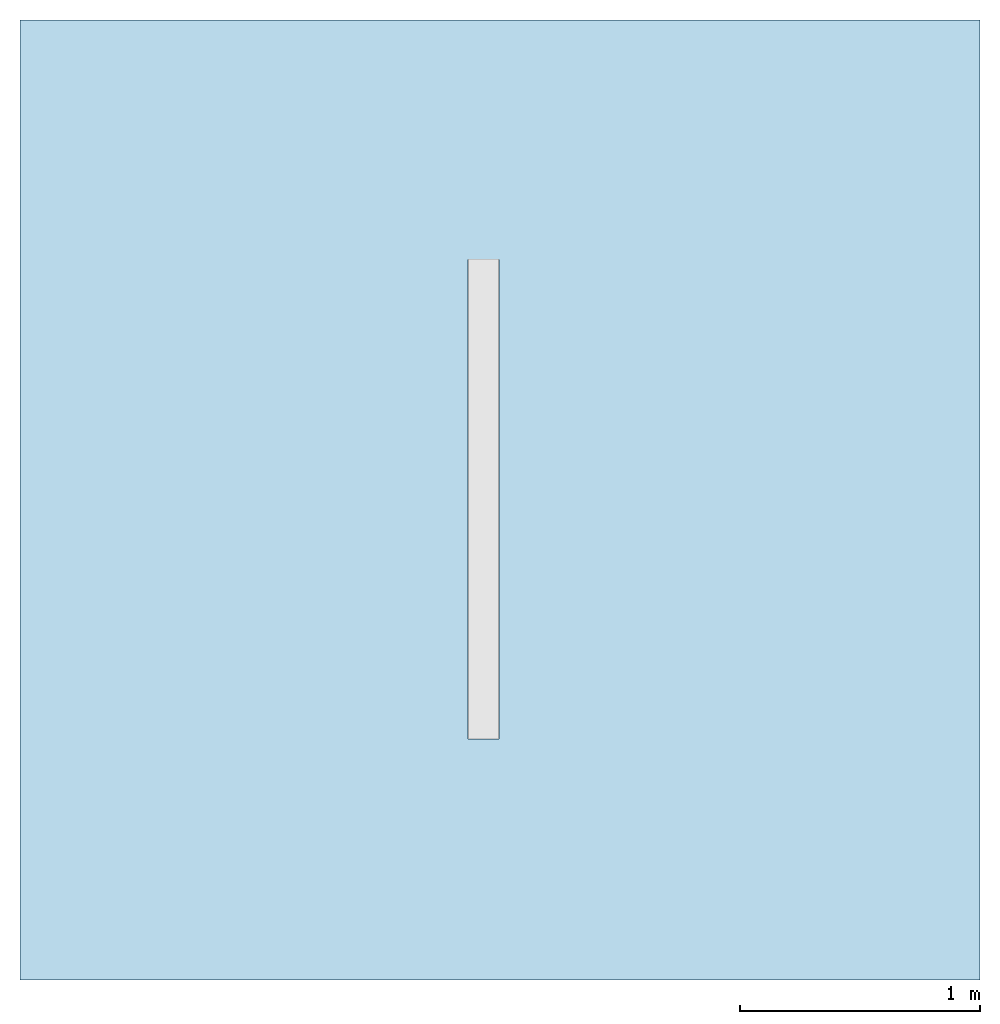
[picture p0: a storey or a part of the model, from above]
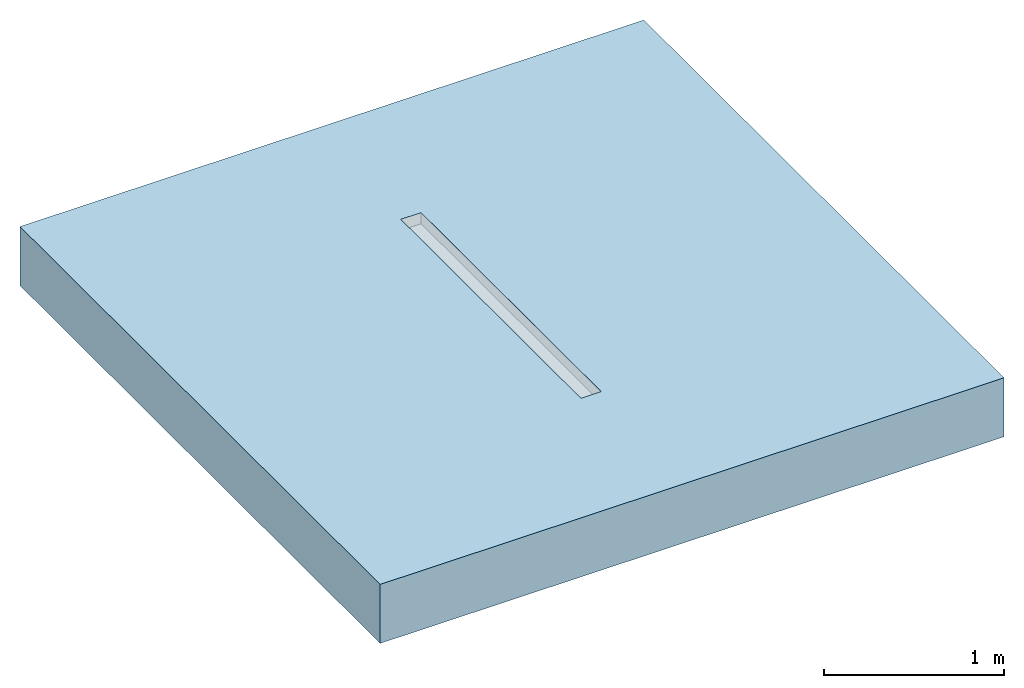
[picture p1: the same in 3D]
Properties of the parts of a building model (IFC2X3)

# File
Description: ViewDefinition [CoordinationView]
File name: Project Number
Time: 2014-06-06T14:55:17
Written by: The EXPRESS Data Manager Version 5.01.0100.02.64mod : 6 Jun 2012
Made in: 20130308_1515(x64) - Exporter 2014.0.2013.0308 - Default UI
Comment: STEP Physical File produced by: The EXPRESS Data Manager Version 5.01.0100.02.64mod : 6 Jun 2012 * Module: EDMstepFileFactory/EDMstandAlone * Creation date: Fri Jun 06 14:55:17 2014 * Host: IN-BLR-PC-0010 * Database: C:\Users\palleri\AppData\Local\Temp\{A1F0F1A7-A8EC-4AB1-B1F4-9037619E79AD}\ifc * Database version: 5507 * Database creation date: Fri Jun 06 14:55:12 2014 * Schema: IFC2X3 * Model: DataRepository.ifc * Model creation date: Fri Jun 06 14:55:12 2014 * Header model: DataRepository.ifc_HeaderModel * Header model creation date: Fri Jun 06 14:55:12 2014 * EDMuser: sdai-user * EDMgroup: sdai-group * License ID and type: 5605 : Permanent license. Expiry date: * EDMstepFileFactory options: 020000

# IfcProject, Project Number
LongName: Project Name; Phase: Project Status

# IfcSite, Default
RefLatitude: 42, 21, 30, 344238; RefLongitude: -71, -3, -35, -194702; RefElevation: 0 mm

# IfcBuilding
Pset_BuildingCommon - NumberOfStoreys: 1
Other - Project Issue Date: Issue Date; Client Name: Owner; Project Number: Project Number; Project Name: Project Name; Project Address: ## Street City, State Zip; Project Status: Project Status

# IfcBuildingStorey, Level 1
LongName: Level 1; Elevation: 0 mm
Constraints - Elevation Base: Project Base Point; Elevation: 0 mm
Graphics - Symbol at End 2 Default: yes; Color: 0; Symbol at End 1 Default: no; Line Weight: 1; Line Pattern: Center; Symbol: M_Level Head - Circle: M_Level Head - Circle
Identity Data - Building Story: yes; Structural: no; Name: Level 1
Dimensions - Computation Height: 0 mm

# IfcFlowTerminal: 36980 - Fixed Height Channel - Shallow Section - 2000mm LG - Invert Depth 75mm, ACO Freedeck Fixed Height Channel Intermediate Section Galvanized Steel:36980 - Fixed Height Channel - Shallow Section - 2000mm LG - Invert Depth 75mm:310971
In: Level 1
Material: Galvanized Steel
Construction - End Plate Invert 2: no; 00276 - Grating - Slotted Grating - Galvanised Steel - 1000mm long: no; End Plate Invert 1: no; 00277 - Grating - Slotted Grating - Galvanised Steel - 500mm long: no; 36952 - Grating - Plain Mesh - Galvanised Steel - 500mm long: no; 36953 - Grating - Plain Mesh - Galvanised Steel - 1000mm long: yes
Identity Data - Mark: 28; Watermark2: This file is water marked and users are prohibited to reproduce, adapt, distribute this information; Watermarked By: www.acobd.com; Watermark1: This file is the property of ACO Technologies PLC; E-mail Sales: abdcommercial@aco.co.uk; E-mail Technical: abdtechnical@aco.co.uk; Watermarked With: BIM Manager Premium Suite; Address: ACO Business Centre, Caxton Road, Bedford, MK41 0LF; Telephone: +44 (0)1462 816666; Website: www.acobd.com; Manufacturer: ACO Building Drainage; Fax: +44 (0)1462 851490
Phasing - Phase Created: New Construction
Constraints - Moves With Nearby Elements: no; Level: Level: Level 1
Pset_ManufacturerTypeInformation - Manufacturer: ACO Building Drainage
General - Channel Recycled Material Content: 25 - 30 %; Channel Recyclable: Fully recyclable; Load Class: A15; Product Description: ACO FreeDeck Fixed Height Channel - Intermediate Section; NBS Specification: NBS Section R10 Gravity Rainwater Drainage Systems, Subsection 365; Channel Colour: Galvanised; Maintenance Guidelines: X:\Electronic Literature\ABD Electronic Literature\Roof and Balcony Drainage\ACO Freedeck Brochure.pdf; Product Standard: BS EN 1433:2002, CE marked; Product Code: 36980; Channel Material: Hot Dipped Galvanised Steel; Product Range: ACO Freedeck; Installation Guidelines: X:\Electronic Literature\ABD Electronic Literature\Roof and Balcony Drainage\ACO Freedeck Brochure.pdf; Price: POA - contact ACO; Weight (Kg): 4.8kg; Dimensions (LxWxH): 2000 x 130 x 75; Product Type: Linear Deck Drainage System
Model Properties - Grating Product Code 00277: Load Class A15 - Slotted Grating - 10 x 80mm Slot - Galvanized Steel - 500mm long - 1.0kg; Grating Product Code 00276: Load Class A15 - Slotted Grating - 10 x 80mm Slot - Galvanized Steel - 1000mm long - 2.2kg; Grating Product Code 36952: Load Class A15 - Mesh Grating - 14mm x 30mm Mesh - Galvanized Steel - 500mm long - 1.6kg; End Plate Product Code 36983: End Plate - Galvanized Steel for Invert Depth - 75mm - 0.07Kg; Grating Product Code 36953: Load Class A15 - Mesh Grating - 14mm x 30mm Mesh - Galvanized Steel - 1000mm long - 3.0kg
Other - Nos: 64; Side Void: 8
Materials and Finishes - Material: Galvanized Steel
Dimensions - Grating End Length: 2000 mm; Height: 75 mm; Channel End Length: -2000 mm

# IfcSlab: Floor:Generic Floor - 400mm, Floor:Generic Floor - 400mm:193825
In: Level 1
PredefinedType: FLOOR; Material: Concrete, Broom Finish 400 mm
Structural - Enable Analytical Model: no; Structural: no
Dimensions - Area: 16 m2; Thickness: 400 mm; Volume: 6.3805 m3; Perimeter: 16000 mm
Constraints - Height Offset From Level: 0 mm; Level: Level: Level 1; Room Bounding: yes; Related to Mass: no
Phasing - Phase Created: New Construction
Pset_SlabCommon - Reference: Generic Floor - 400mm; IsExternal: no; LoadBearing: yes; ThermalTransmittance: 2.615 kg/K/s3; PitchAngle: 0 deg
Analytical Properties - Thermal mass: 604440; Roughness: 1; Thermal Resistance (R): 0.382409; Absorptance: 0.1; Heat Transfer Coefficient (U): 2.615
Construction - Function: Interior; Default Thickness: 400 mm
Materials and Finishes - Structural Material: Concrete, Broom Finish
Graphics - Coarse Scale Fill Color: 0
